###############################################################
#  Generated by:      Cadence Innovus 25.11-s102_1
#  OS:                Linux x86_64(Host ID ece-rschsrv.ece.gatech.edu)
#  Generated on:      Sat Feb 14 12:56:17 2026
#  Design:            counter_16bit
#  Command:           write_lef_abstract ./output/counter_16bit.lef
###############################################################

VERSION 5.8 ;

BUSBITCHARS "[]" ;
DIVIDERCHAR "/" ;

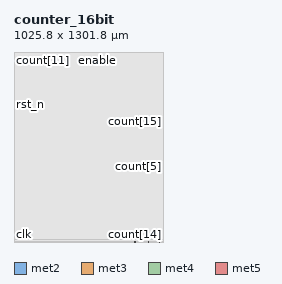
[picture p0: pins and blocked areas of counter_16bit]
MACRO counter_16bit
  CLASS BLOCK ;
  SIZE 1025.800000 BY 1301.800000 ;
  FOREIGN counter_16bit 0.000000 0.000000 ;
  ORIGIN 0 0 ;
  SYMMETRY X Y R90 ;
  PIN clk
    DIRECTION INPUT ;
    USE SIGNAL ;
    ANTENNAPARTIALMETALSIDEAREA 1.568 LAYER met2  ;
    ANTENNAPARTIALMETALAREA 0.3458 LAYER met2  ;
    ANTENNAPARTIALCUTAREA 0.04 LAYER via2  ;
    ANTENNAPARTIALMETALSIDEAREA 1.808 LAYER met3  ;
    ANTENNAPARTIALMETALAREA 0.2519 LAYER met3  ;
    ANTENNAPARTIALCUTAREA 0.04 LAYER via3  ;
    ANTENNAMODEL OXIDE1 ;
    ANTENNAMAXSIDEAREACAR 395.149 LAYER met4  ;
    ANTENNAMAXAREACAR 74.9911 LAYER met4  ;
    ANTENNAPARTIALMETALSIDEAREA 177.12 LAYER met4  ;
    ANTENNAPARTIALMETALAREA 32.4216 LAYER met4  ;
    ANTENNAGATEAREA 2.52 LAYER met4  ;
    PORT
      LAYER met2 ;
        RECT 0.000000 10.050000 0.485000 10.190000 ;
    END
  END clk
  PIN rst_n
    DIRECTION INPUT ;
    USE SIGNAL ;
    ANTENNAPARTIALMETALSIDEAREA 1.764 LAYER met2  ;
    ANTENNAPARTIALMETALAREA 0.385 LAYER met2  ;
    ANTENNAPARTIALCUTAREA 0.04 LAYER via2  ;
    ANTENNAMODEL OXIDE1 ;
    ANTENNAMAXSIDEAREACAR 349.902 LAYER met3  ;
    ANTENNAMAXAREACAR 66.8286 LAYER met3  ;
    ANTENNAPARTIALMETALSIDEAREA 53.36 LAYER met3  ;
    ANTENNAPARTIALMETALAREA 9.9168 LAYER met3  ;
    ANTENNAGATEAREA 0.1575 LAYER met3  ;
    PORT
      LAYER met2 ;
        RECT 0.000000 940.630000 0.485000 940.770000 ;
    END
  END rst_n
  PIN enable
    DIRECTION INPUT ;
    USE SIGNAL ;
    ANTENNAPARTIALMETALSIDEAREA 22.554 LAYER met2  ;
    ANTENNAPARTIALMETALAREA 4.543 LAYER met2  ;
    ANTENNAPARTIALCUTAREA 0.04 LAYER via2  ;
    ANTENNAMODEL OXIDE1 ;
    ANTENNAMAXSIDEAREACAR 409.094 LAYER met3  ;
    ANTENNAMAXAREACAR 79.407 LAYER met3  ;
    ANTENNAPARTIALMETALSIDEAREA 816.048 LAYER met3  ;
    ANTENNAPARTIALMETALAREA 152.569 LAYER met3  ;
    ANTENNAGATEAREA 2.93025 LAYER met3  ;
    PORT
      LAYER met2 ;
        RECT 569.870000 1301.315000 570.010000 1301.800000 ;
    END
  END enable
  PIN count[15]
    DIRECTION OUTPUT ;
    USE SIGNAL ;
    ANTENNAPARTIALMETALSIDEAREA 37.6985 LAYER met2  ;
    ANTENNAPARTIALMETALAREA 7.5849 LAYER met2  ;
    ANTENNADIFFAREA 0.5292 LAYER met2  ;
    PORT
      LAYER met2 ;
        RECT 1025.315000 826.550000 1025.800000 826.690000 ;
    END
  END count[15]
  PIN count[14]
    DIRECTION OUTPUT ;
    USE SIGNAL ;
    ANTENNAPARTIALMETALSIDEAREA 21.5985 LAYER met2  ;
    ANTENNAPARTIALMETALAREA 4.3649 LAYER met2  ;
    ANTENNADIFFAREA 1.0584 LAYER met2  ;
    PORT
      LAYER met2 ;
        RECT 921.310000 0.000000 921.450000 0.485000 ;
    END
  END count[14]
  PIN count[13]
    DIRECTION OUTPUT ;
    USE SIGNAL ;
    ANTENNAMODEL OXIDE1 ;
    ANTENNAMAXSIDEAREACAR 45.1975 LAYER met2  ;
    ANTENNAMAXAREACAR 9.60379 LAYER met2  ;
    ANTENNAPARTIALMETALSIDEAREA 23.8525 LAYER met2  ;
    ANTENNAPARTIALMETALAREA 4.8157 LAYER met2  ;
    ANTENNADIFFAREA 1.0584 LAYER met2  ;
    ANTENNAGATEAREA 0.567 LAYER met2  ;
    PORT
      LAYER met2 ;
        RECT 0.000000 9.590000 0.485000 9.730000 ;
    END
  END count[13]
  PIN count[12]
    DIRECTION OUTPUT ;
    USE SIGNAL ;
    ANTENNAPARTIALMETALSIDEAREA 51.032 LAYER met3  ;
    ANTENNAPARTIALMETALAREA 9.5694 LAYER met3  ;
    ANTENNADIFFAREA 0.5292 LAYER met3  ;
    PORT
      LAYER met3 ;
        RECT 0.000000 10.230000 0.800000 10.530000 ;
    END
  END count[12]
  PIN count[11]
    DIRECTION OUTPUT ;
    USE SIGNAL ;
    ANTENNAPARTIALMETALSIDEAREA 28.296 LAYER met3  ;
    ANTENNAPARTIALMETALAREA 5.3064 LAYER met3  ;
    ANTENNADIFFAREA 1.0584 LAYER met3  ;
    PORT
      LAYER met3 ;
        RECT 29.290000 1301.000000 29.590000 1301.800000 ;
    END
  END count[11]
  PIN count[10]
    DIRECTION OUTPUT ;
    USE SIGNAL ;
    ANTENNAPARTIALMETALSIDEAREA 311.096 LAYER met3  ;
    ANTENNAPARTIALMETALAREA 58.3314 LAYER met3  ;
    ANTENNADIFFAREA 1.0584 LAYER met3  ;
    PORT
      LAYER met3 ;
        RECT 1025.000000 1292.450000 1025.800000 1292.750000 ;
    END
  END count[10]
  PIN count[9]
    DIRECTION OUTPUT ;
    USE SIGNAL ;
    ANTENNAPARTIALMETALSIDEAREA 266.984 LAYER met3  ;
    ANTENNAPARTIALMETALAREA 50.0604 LAYER met3  ;
    ANTENNADIFFAREA 1.0584 LAYER met3  ;
    PORT
      LAYER met3 ;
        RECT 996.670000 0.000000 996.970000 0.800000 ;
    END
  END count[9]
  PIN count[8]
    DIRECTION OUTPUT ;
    USE SIGNAL ;
    ANTENNAPARTIALMETALSIDEAREA 51.832 LAYER met3  ;
    ANTENNAPARTIALMETALAREA 9.7194 LAYER met3  ;
    ANTENNADIFFAREA 0.5292 LAYER met3  ;
    PORT
      LAYER met3 ;
        RECT 0.000000 9.620000 0.800000 9.920000 ;
    END
  END count[8]
  PIN count[7]
    DIRECTION OUTPUT ;
    USE SIGNAL ;
    ANTENNAPARTIALMETALSIDEAREA 75.8 LAYER met4  ;
    ANTENNAPARTIALMETALAREA 14.2134 LAYER met4  ;
    ANTENNADIFFAREA 0.5292 LAYER met4  ;
    PORT
      LAYER met4 ;
        RECT 0.000000 10.230000 0.800000 10.530000 ;
    END
  END count[7]
  PIN count[6]
    DIRECTION OUTPUT ;
    USE SIGNAL ;
    ANTENNAPARTIALMETALSIDEAREA 72.312 LAYER met4  ;
    ANTENNAPARTIALMETALAREA 13.5594 LAYER met4  ;
    ANTENNADIFFAREA 1.0584 LAYER met4  ;
    PORT
      LAYER met4 ;
        RECT 256.070000 1301.000000 256.370000 1301.800000 ;
    END
  END count[6]
  PIN count[5]
    DIRECTION OUTPUT ;
    USE SIGNAL ;
    ANTENNAPARTIALMETALSIDEAREA 197.912 LAYER met4  ;
    ANTENNAPARTIALMETALAREA 37.1094 LAYER met4  ;
    ANTENNADIFFAREA 1.0584 LAYER met4  ;
    PORT
      LAYER met4 ;
        RECT 1025.000000 519.580000 1025.800000 519.880000 ;
    END
  END count[5]
  PIN count[4]
    DIRECTION OUTPUT ;
    USE SIGNAL ;
    ANTENNAPARTIALMETALSIDEAREA 25.072 LAYER met4  ;
    ANTENNAPARTIALMETALAREA 4.7019 LAYER met4  ;
    ANTENNADIFFAREA 0.5292 LAYER met4  ;
    PORT
      LAYER met4 ;
        RECT 0.000000 9.620000 0.800000 9.920000 ;
    END
  END count[4]
  PIN count[3]
    DIRECTION OUTPUT ;
    USE SIGNAL ;
    ANTENNAPARTIALMETALSIDEAREA 14.544 LAYER met5  ;
    ANTENNAPARTIALMETALAREA 9.696 LAYER met5  ;
    ANTENNADIFFAREA 0.5292 LAYER met5  ;
    PORT
      LAYER met5 ;
        RECT 0.000000 10.800000 2.500000 12.400000 ;
    END
  END count[3]
  PIN count[2]
    DIRECTION OUTPUT ;
    USE SIGNAL ;
    ANTENNAPARTIALMETALSIDEAREA 105.156 LAYER met5  ;
    ANTENNAPARTIALMETALAREA 70.104 LAYER met5  ;
    ANTENNADIFFAREA 1.0584 LAYER met5  ;
    PORT
      LAYER met5 ;
        RECT 611.505000 1299.300000 613.105000 1301.800000 ;
    END
  END count[2]
  PIN count[1]
    DIRECTION OUTPUT ;
    USE SIGNAL ;
    ANTENNAPARTIALMETALSIDEAREA 6.192 LAYER met5  ;
    ANTENNAPARTIALMETALAREA 4.128 LAYER met5  ;
    ANTENNADIFFAREA 1.0584 LAYER met5  ;
    PORT
      LAYER met5 ;
        RECT 827.985000 0.000000 829.585000 2.500000 ;
    END
  END count[1]
  PIN count[0]
    DIRECTION OUTPUT ;
    USE SIGNAL ;
    ANTENNADIFFAREA 0.5292 LAYER met5  ;
    PORT
      LAYER met5 ;
        RECT 0.000000 7.140000 2.500000 8.740000 ;
    END
  END count[0]
  OBS
    LAYER met1 ;
      RECT 0.000000 0.000000 1025.800000 1301.800000 ;
    LAYER met2 ;
      RECT 570.150000 1301.175000 1025.800000 1301.800000 ;
      RECT 0.000000 1301.175000 569.730000 1301.800000 ;
      RECT 0.000000 940.910000 1025.800000 1301.175000 ;
      RECT 0.625000 940.490000 1025.800000 940.910000 ;
      RECT 0.000000 826.830000 1025.800000 940.490000 ;
      RECT 0.000000 826.410000 1025.175000 826.830000 ;
      RECT 0.000000 10.330000 1025.800000 826.410000 ;
      RECT 0.625000 9.910000 1025.800000 10.330000 ;
      RECT 0.000000 9.870000 1025.800000 9.910000 ;
      RECT 0.625000 9.450000 1025.800000 9.870000 ;
      RECT 0.000000 0.625000 1025.800000 9.450000 ;
      RECT 921.590000 0.000000 1025.800000 0.625000 ;
      RECT 0.000000 0.000000 921.170000 0.625000 ;
    LAYER met3 ;
      RECT 29.890000 1300.700000 1025.800000 1301.800000 ;
      RECT 0.000000 1300.700000 28.990000 1301.800000 ;
      RECT 0.000000 1293.050000 1025.800000 1300.700000 ;
      RECT 0.000000 1292.150000 1024.700000 1293.050000 ;
      RECT 0.000000 10.830000 1025.800000 1292.150000 ;
      RECT 1.100000 9.320000 1025.800000 10.830000 ;
      RECT 0.000000 1.100000 1025.800000 9.320000 ;
      RECT 997.270000 0.000000 1025.800000 1.100000 ;
      RECT 0.000000 0.000000 996.370000 1.100000 ;
    LAYER met4 ;
      RECT 256.670000 1300.700000 1025.800000 1301.800000 ;
      RECT 0.000000 1300.700000 255.770000 1301.800000 ;
      RECT 0.000000 520.180000 1025.800000 1300.700000 ;
      RECT 0.000000 519.280000 1024.700000 520.180000 ;
      RECT 0.000000 10.830000 1025.800000 519.280000 ;
      RECT 1.100000 9.320000 1025.800000 10.830000 ;
      RECT 0.000000 0.000000 1025.800000 9.320000 ;
    LAYER met5 ;
      RECT 614.705000 1297.700000 1025.800000 1301.800000 ;
      RECT 0.000000 1297.700000 609.905000 1301.800000 ;
      RECT 0.000000 14.000000 1025.800000 1297.700000 ;
      RECT 4.100000 5.540000 1025.800000 14.000000 ;
      RECT 0.000000 4.100000 1025.800000 5.540000 ;
      RECT 831.185000 0.000000 1025.800000 4.100000 ;
      RECT 0.000000 0.000000 826.385000 4.100000 ;
  END
END counter_16bit

END LIBRARY
